VERSION 5.8 ;
BUSBITCHARS "[]" ;
DIVIDERCHAR "/" ;
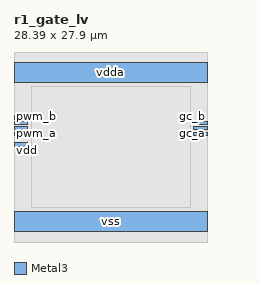
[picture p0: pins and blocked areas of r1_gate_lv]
MACRO r1_gate_lv
  CLASS BLOCK ;
  ORIGIN 0 0 ;
  FOREIGN r1_gate_lv 0 0 ;
  SIZE 28.390 BY 27.900 ;
  SYMMETRY X Y ;
  PIN pwm_a
    DIRECTION INOUT ;
    USE SIGNAL ;
    PORT
      LAYER Metal3 ;
        RECT 0.000 15.650 2.000 16.150 ;
    END
  END pwm_a
  PIN pwm_b
    DIRECTION INOUT ;
    USE SIGNAL ;
    PORT
      LAYER Metal3 ;
        RECT 0.000 17.250 2.000 17.750 ;
    END
  END pwm_b
  PIN pwm_c
    DIRECTION INOUT ;
    USE SIGNAL ;
    PORT
      LAYER Metal3 ;
        RECT 0.000 18.050 2.000 18.550 ;
    END
  END pwm_c
  PIN gate_en
    DIRECTION INOUT ;
    USE SIGNAL ;
    PORT
      LAYER Metal3 ;
        RECT 0.000 16.450 2.000 16.950 ;
    END
  END gate_en
  PIN gc_a
    DIRECTION INOUT ;
    USE SIGNAL ;
    PORT
      LAYER Metal3 ;
        RECT 26.390 15.650 28.390 16.150 ;
    END
  END gc_a
  PIN gc_b
    DIRECTION INOUT ;
    USE SIGNAL ;
    PORT
      LAYER Metal3 ;
        RECT 26.390 17.250 28.390 17.750 ;
    END
  END gc_b
  PIN gc_c
    DIRECTION INOUT ;
    USE SIGNAL ;
    PORT
      LAYER Metal3 ;
        RECT 26.390 16.450 28.390 16.950 ;
    END
  END gc_c
  PIN vss
    DIRECTION INOUT ;
    USE GROUND ;
    PORT
      LAYER Metal3 ;
        RECT 0.000 1.500 28.390 4.500 ;
    END
  END vss
  PIN vdda
    DIRECTION INOUT ;
    USE POWER ;
    PORT
      LAYER Metal3 ;
        RECT 0.000 23.400 28.390 26.400 ;
    END
  END vdda
  PIN vdd
    DIRECTION INOUT ;
    USE POWER ;
    PORT
      LAYER Metal3 ;
        RECT 0.000 14.080 2.000 14.580 ;
    END
  END vdd
  OBS
    LAYER Metal1 ;
      RECT 0.000 0.000 28.390 27.900 ;
    LAYER Metal2 ;
      RECT 0.000 0.000 28.390 27.900 ;
    LAYER Metal3 ;
      RECT 2.500 5.000 25.890 22.900 ;
  END
END r1_gate_lv
END LIBRARY
